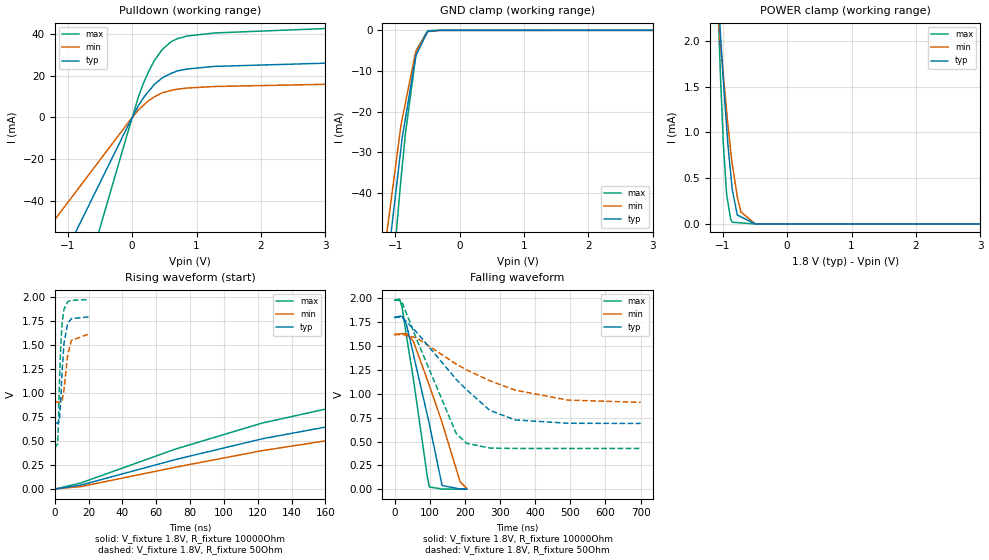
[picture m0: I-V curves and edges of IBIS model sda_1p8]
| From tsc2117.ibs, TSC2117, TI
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|   sda_1p8 Model
[Model]   sda_1p8
Model_type   I/O_open_drain
Polarity   Inverting
Vinl = 0.54
Vinh = 1.26
Vmeas = 0.9
Vref = 1.8
Cref = 400pF
Rref = 10000
|   typ   min   max
|   (nom PVT)   (fast PVT)   (slow PVT)
|C_comp from frequency sweep method (F=400KHz)
|C_comp   5.967e-10   5.938e-10   6.030e-10
|ON state : BUFFER OUTPUT TURNED LOW
|C_comp   5.967e-10   5.938e-10   6.030e-10
|OFF state: BUFFER IN HIGH IMPEDANCE
|C_comp   3.660e-12   3.640e-12   3.676e-12
|C_comp from LC tank measurement(L=1nH)
|Resonant Frequency(Hz)   4.500e+09   4.530e+09   4.490e+09
C_comp   1.252e-12   1.236e-12   1.258e-12
|ON state : BUFFER OUTPUT TURNED LOW
|Resonant Frequency(Hz)   4.500e+09   4.530e+09   4.490e+09
|C_comp   1.252e-12   1.236e-12   1.258e-12
|OFF state: BUFFER IN HIGH IMPEDANCE
|Resonant Frequency(Hz)   4.620e+09   4.640e+09   4.617e+09
|C_comp   1.188e-12   1.178e-12   1.189e-12
| Where nom  PVT is Nominal Process, 1.8V, 48C
|   Fast PVT is Strong Process,  1.98V, -40C
|   Slow PVT is Weak Process,   1.62V, 108C
[Model Spec]
|Subparameter   typ   min   max
Vinh   1.26   1.134   1.386
Vinl   0.54   0.486   0.594
[Voltage Range]   1.8   1.62   1.98
|Ambient Temperature   25   85   -40
|Junction Temperature
[Temperature Range]   48   108   -40
[Pullup Reference]   1.8   1.62   1.98
[Pulldown Reference]   0   0   0
[Power Clamp Reference]   1.8   1.62   1.98
[GND Clamp Reference]   0   0   0
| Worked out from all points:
|   slope of the pulldown table from 0 to 0.27 V, typ, clamps not added: 20.6 ohm
|   GND clamp passes 1 mA (typ) near -0.52 V on its own axis
|   POWER clamp passes 1 mA (typ) near -0.93 V on its own axis
|   falling waveform, V_fixture 1.8V, R_fixture 10000Ohm: 20-80 % time 65.4ns typ, 88.8ns min, 49.7ns max; typ from 1.8 V to 0.003 V
|   rising waveform, V_fixture 1.8V, R_fixture 10000Ohm: 20-80 % time 454ns typ, 530ns min, 375ns max; typ from 0.003 V to 1.8 V
|   falling waveform, V_fixture 1.8V, R_fixture 50Ohm: 20-80 % time 165ns typ, 226ns min, 106ns max; typ from 1.8 V to 0.69 V
|   rising waveform, V_fixture 1.8V, R_fixture 50Ohm: 20-80 % time 2.3ns typ, 2.86ns min, 1.81ns max; typ from 0.69 V to 1.79 V
[Pulldown]
|   Voltage   I(typ)   I(min)   I(max)
-1.8V     -112.9mA   -73.46mA   -191.1mA
-72mV     -4.517mA   -2.938mA   -7.643mA
95.04mV   5.515mA    3.506mA    9.594mA
168.3mV   9.101mA    5.635mA    15.82mA
251.5mV   12.38mA    7.971mA    21.78mA
348.5mV   15.93mA    9.897mA    27.41mA
463.3mV   18.89mA    11.79mA    32.41mA
601.9mV   21.09mA    12.95mA    36.24mA
698.9mV   22.27mA    13.55mA    37.73mA
855.4mV   23.22mA    14.1mA     39.04mA
1.277V    24.47mA    14.84mA    40.49mA
3.6V      26.55mA    16.24mA    43.36mA
[GND Clamp]
|   Voltage   I(typ)   I(min)   I(max)
-1.8V     -240.5mA   -130.8mA   -381.7mA
-1.135V   -59.46mA   -50.42mA   -77.52mA
-910.4mV  -29.03mA   -23.35mA   -36.59mA
-892.8mV  -26.66mA   -21.92mA   -33.72mA
-841.5mV  -21.74mA   -17.87mA   -25.51mA
-686.9mV  -6.885mA   -5.643mA   -7.097mA
-680.4mV  -6.263mA   -5.29mA    -6.326mA
-667.3mV  -5.837mA   -4.938mA   -4.761mA
-495mV    -260.5uA   -323.8uA   -73.08uA
-307.8mV  -1.423uA   -3.756uA   -100.3nA
3.6V      0A         0A         0A
[POWER Clamp]
|   Voltage   I(typ)   I(min)   I(max)
-1.8V     11.89mA    8.634mA    19.35mA
-1.085V   2.686mA    2.385mA    2.616mA
-1.035V   2.081mA    1.973mA    1.633mA
-990mV    1.577mA    1.628mA    881.4uA
-938.5mV  1.059mA    1.234mA    323.2uA
-919.8mV  874.1uA    1.094mA    242.3uA
-875.2mV  549.7uA    793.1uA    49.36uA
-851.4mV  377uA      658uA      18.85uA
-774mV    98.6uA     299.2uA    14.76uA
-717.7mV  78.69uA    132uA      11.78uA
-494.1mV  14.85nA    598.8nA    0A
3.6V      0A         0A         0A
[Ramp]
R_load = 10000
|   typ   min   max
dV/dt_r   1.07577/4.53944e-07   0.963828/5.29668e-07   1.18621/3.74258e-07
dV/dt_f   1.07809/6.54273e-08   0.965385/8.87865e-08   1.18692/4.97473e-08
[Falling Waveform]
V_fixture = 1.8V
V_fixture_min = 1.62V
V_fixture_max = 1.98V
R_fixture = 10000Ohm
|   Time   V(typ)   V(min)   V(max)
0s        1.8V       1.62V      1.98V
14.06ns   1.812V     1.626V     1.992V
21.7ns    1.81V      1.631V     1.902V
34.14ns   1.721V     1.63V      1.599V
53.44ns   1.414V     1.55V      1.157V
93.66ns   768.6mV    1.141V     122.9mV
98.92ns   681.4mV    1.087V     25.25mV
135.2ns   39.63mV    699.4mV    2.177mV
186.4ns   3.511mV    79.5mV     1.821mV
205ns     3.182mV    11.02mV    1.803mV
[Rising Waveform]
V_fixture = 1.8V
V_fixture_min = 1.62V
V_fixture_max = 1.98V
R_fixture = 10000Ohm
|   Time   V(typ)   V(min)   V(max)
0s        2.854mV    4.008mV    1.79mV
15.6ns    44.68mV    29mV       67.45mV
71.2ns    309.1mV    229.7mV    417.9mV
122.8ns   526.2mV    403mV      690.2mV
238.2ns   902.7mV    716.4mV    1.138V
379.4ns   1.214V     992mV      1.48V
548.6ns   1.45V      1.213V     1.713V
757.8ns   1.615V     1.383V     1.858V
1.086us   1.732V     1.519V     1.944V
2us       1.796V     1.61V      1.979V
[Falling Waveform]
V_fixture = 1.8V
V_fixture_min = 1.62V
V_fixture_max = 1.98V
R_fixture = 50Ohm
|   Time   V(typ)   V(min)   V(max)
0s        1.8V       1.62V      1.98V
14.75ns   1.802V     1.621V     1.979V
22.87ns   1.798V     1.621V     1.943V
63.47ns   1.642V     1.584V     1.564V
175.6ns   1.15V      1.31V      583mV
204.5ns   1.044V     1.251V     482.6mV
270.8ns   827.1mV    1.137V     431.9mV
342.4ns   727.3mV    1.039V     428mV
492.6ns   691.8mV    934.6mV    427.7mV
700ns     689.7mV    910.4mV    427.7mV
[Rising Waveform]
V_fixture = 1.8V
V_fixture_min = 1.62V
V_fixture_max = 1.98V
R_fixture = 50Ohm
|   Time   V(typ)   V(min)   V(max)
0s        689.6mV    908mV      427.7mV
1.74ns    689.6mV    908mV      476.9mV
2.095ns   689.4mV    908mV      637.1mV
2.754ns   722.4mV    908mV      1.106V
3.552ns   932.2mV    907.8mV    1.511V
4.395ns   1.25V      921.3mV    1.74V
5.437ns   1.517V     1.034V     1.871V
7.614ns   1.725V     1.399V     1.951V
9.788ns   1.775V     1.549V     1.966V
20ns      1.794V     1.615V     1.974V
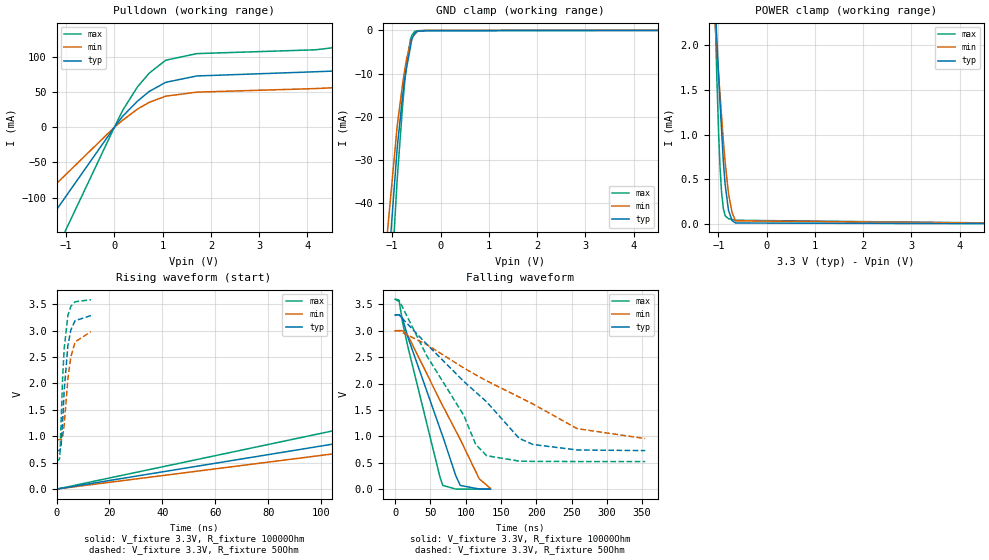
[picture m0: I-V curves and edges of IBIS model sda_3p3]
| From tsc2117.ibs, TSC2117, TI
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|   sda_3p3 Model
[Model]   sda_3p3
Model_type   I/O_open_drain
Polarity   Inverting
Vinl = 0.99
Vinh = 2.31
Vmeas = 1.65
Vref = 3.3
Cref = 400pF
Rref = 10000
|   typ   min   max
|   (nom PVT)   (fast PVT)   (slow PVT)
|C_comp from frequency sweep method (F=400KHz)
|C_comp   5.302e-10   4.865e-10   5.416e-10
|ON state : BUFFER OUTPUT TURNED LOW
|C_comp   5.302e-10   4.865e-10   5.416e-10
|OFF state: BUFFER IN HIGH IMPEDANCE
|C_comp   3.575e-12   3.526e-12   3.580e-12
|C_comp from LC tank measurement(L=1nH)
|Resonant Frequency(Hz)   4.530e+09   4.570e+09   4.527e+09
C_comp   1.236e-12   1.214e-12   1.237e-12
|ON state : BUFFER OUTPUT TURNED LOW
|Resonant Frequency(Hz)   4.530e+09   4.570e+09   4.527e+09
|C_comp   1.236e-12   1.214e-12   1.237e-12
|OFF state: BUFFER IN HIGH IMPEDANCE
|Resonant Frequency(Hz)   4.770e+09   4.790e+09   4.760e+09
|C_comp   1.114e-12   1.105e-12   1.119e-12
| Where nom  PVT is Nominal Process, 3.3V, 48C
|   Fast PVT is Strong Process,  3.6V, -40C
|   Slow PVT is Weak Process,   3V, 108C
[Model Spec]
|Subparameter   typ   min   max
Vinh   2.31   2.1   2.52
Vinl   0.99   0.9   1.08
[Voltage Range]   3.3   3   3.6
|Ambient Temperature   25   85   -40
|Junction Temperature
[Temperature Range]   48   108   -40
[Pullup Reference]   3.3   3   3.6
[Pulldown Reference]   0   0   0
[Power Clamp Reference]   3.3   3   3.6
[GND Clamp Reference]   0   0   0
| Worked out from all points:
|   slope of the pulldown table from 0 to 0.495 V, typ, clamps not added: 13 ohm
|   GND clamp passes 1 mA (typ) near -0.55 V on its own axis
|   POWER clamp passes 1 mA (typ) near -0.93 V on its own axis
|   falling waveform, V_fixture 3.3V, R_fixture 10000Ohm: 20-80 % time 53.1ns typ, 69.2ns min, 41.1ns max; typ from 3.3 V to 0.004 V
|   rising waveform, V_fixture 3.3V, R_fixture 10000Ohm: 20-80 % time 453ns typ, 529ns min, 373ns max; typ from 0.003 V to 3.29 V
|   falling waveform, V_fixture 3.3V, R_fixture 50Ohm: 20-80 % time 115ns typ, 164ns min, 79.7ns max; typ from 3.3 V to 0.732 V
|   rising waveform, V_fixture 3.3V, R_fixture 50Ohm: 20-80 % time 2.18ns typ, 2.59ns min, 1.74ns max; typ from 0.732 V to 3.28 V
[Pulldown]
|   Voltage   I(typ)   I(min)   I(max)
-3.3V     -322.4mA   -220.4mA   -478mA
-3mV      -293.1uA   -200.4uA   -434.6uA
172.8mV   15.63mA    9.923mA    24.04mA
478.8mV   36.99mA    25.74mA    57.32mA
720mV     50.66mA    35.15mA    76.62mA
1.062V    63.63mA    43.96mA    94.99mA
1.706V    72.65mA    49.7mA     104.4mA
4.162V    78.62mA    54.77mA    109.8mA
4.507V    79.54mA    55.84mA    112.6mA
5.148V    86.77mA    60.99mA    125.3mA
5.67V     100.5mA    70.64mA    148.5mA
6.6V      155mA      98.67mA    237.4mA
[GND Clamp]
|   Voltage   I(typ)   I(min)   I(max)
-3.3V     -1.756A    -1.583A    -1.981A
-1.498V   -117.6mA   -94.96mA   -151.4mA
-897.6mV  -27.23mA   -22.13mA   -34.46mA
-788.4mV  -15.45mA   -12.65mA   -17.84mA
-745.8mV  -11.34mA   -9.432mA   -12.44mA
-698.4mV  -8.438mA   -6.377mA   -7.366mA
-622.8mV  -3.816mA   -2.95mA    -2.159mA
-590.7mV  -1.853mA   -1.714mA   -1.121mA
-532.8mV  -666.4uA   -905.1uA   -230.1uA
-474mV    -201.1uA   -197.3uA   -92.23uA
-285mV    -120.3uA   -2.039uA   -5.286uA
6.6V      0A         0A         0A
[POWER Clamp]
|   Voltage   I(typ)   I(min)   I(max)
-3.3V     32.35mA    22.57mA    56.44mA
-1.092V   2.8mA      2.46mA     2.906mA
-1.033V   2.101mA    1.972mA    1.686mA
-993.6mV  1.657mA    1.668mA    1.017mA
-964.8mV  1.359mA    1.451mA    640.5uA
-932.4mV  1.048mA    1.207mA    355.4uA
-896.4mV  705.6uA    935.8uA    174.6uA
-858mV    438.3uA    688.4uA    92.2uA
-788.7mV  152.2uA    339.5uA    59.13uA
-714mV    36.66uA    125.5uA    49.1uA
-643.5mV  10.58uA    34.75uA    41.33uA
6.6V      0A         0A         0A
[Ramp]
R_load = 10000
|   typ   min   max
dV/dt_r   1.97353/4.52751e-07   1.78696/5.29156e-07   2.15642/3.72591e-07
dV/dt_f   1.97748/5.31713e-08   1.78868/6.92696e-08   2.15749/4.10977e-08
[Falling Waveform]
V_fixture = 3.3V
V_fixture_min = 3V
V_fixture_max = 3.6V
R_fixture = 10000Ohm
|   Time   V(typ)   V(min)   V(max)
0s        3.3V       3V         3.598V
5.87ns    3.304V     3.003V     3.551V
10.68ns   3.225V     3.002V     3.153V
18.04ns   2.88V      2.914V     2.7V
63.82ns   1.139V     1.675V     218.2mV
67.55ns   1V         1.578V     73.76mV
86.06ns   253.1mV    1.104V     3.907mV
92.31ns   72.81mV    942.9mV    3.251mV
119.2ns   5.324mV    196.8mV    2.525mV
135ns     4.173mV    18.86mV    2.437mV
[Rising Waveform]
V_fixture = 3.3V
V_fixture_min = 3V
V_fixture_max = 3.6V
R_fixture = 10000Ohm
|   Time   V(typ)   V(min)   V(max)
0s        3.377mV    4.491mV    2.376mV
113.4ns   926.8mV    725.7mV    1.199V
169.6ns   1.299V     1.032V     1.649V
230.4ns   1.636V     1.317V     2.042V
374.6ns   2.226V     1.839V     2.688V
546.2ns   2.665V     2.255V     3.121V
752.8ns   2.963V     2.564V     3.379V
1.08us    3.176V     2.813V     3.535V
1.438us   3.259V     2.926V     3.582V
2us       3.293V     2.983V     3.596V
[Falling Waveform]
V_fixture = 3.3V
V_fixture_min = 3V
V_fixture_max = 3.6V
R_fixture = 50Ohm
|   Time   V(typ)   V(min)   V(max)
0s        3.3V       3V         3.6V
5.4ns     3.302V     3.001V     3.581V
44.3ns    2.753V     2.743V     2.539V
97.5ns    2.038V     2.294V     1.394V
114.1ns   1.84V      2.167V     849.7mV
129.6ns   1.656V     2.053V     636mV
175.6ns   965.5mV    1.745V     533.4mV
195ns     848.8mV    1.616V     528.2mV
257.8ns   744.4mV    1.148V     525.5mV
354.2ns   732.1mV    960.1mV    525.4mV
[Rising Waveform]
V_fixture = 3.3V
V_fixture_min = 3V
V_fixture_max = 3.6V
R_fixture = 50Ohm
|   Time   V(typ)   V(min)   V(max)
0s        731.6mV    937mV      525.4mV
1.121ns   731.8mV    937mV      572.6mV
1.371ns   741.9mV    937mV      733.5mV
1.744ns   832.9mV    937.6mV    1.287V
2.266ns   1.227V     979.1mV    2.055V
2.876ns   1.852V     1.205V     2.652V
4.301ns   2.721V     2.092V     3.288V
5.403ns   3.01V      2.499V     3.459V
7.003ns   3.186V     2.785V     3.545V
13ns      3.284V     2.98V      3.584V
